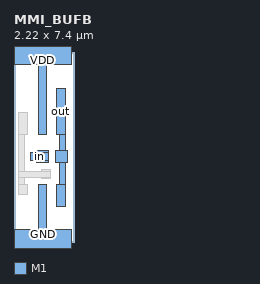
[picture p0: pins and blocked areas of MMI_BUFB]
MACRO MMI_BUFB
	CLASS CORE ;
	FOREIGN MMI_BUFB 0 0 ;
	SIZE 2.22 BY 7.4 ;
	SYMMETRY X Y ;
	SITE CORE1 ;
	PIN out
		DIRECTION output ;
		USE SIGNAL ;
		PORT
			LAYER M1 ;
			RECT 1.66 4.2 2 5.96 ;
			LAYER M1 ;
			RECT 1.77 3.555 2 4.2 ;
			LAYER M1 ;
			RECT 1.625 3.105 2.075 3.555 ;
			LAYER M1 ;
			RECT 1.77 2.23 2 3.105 ;
			LAYER M1 ;
			RECT 1.66 1.39 2 2.23 ;
		END
		AntennaDiffArea 1.3248 ;
	END out
	PIN GND
		DIRECTION inout ;
		USE GROUND ;
		PORT
			LAYER M1 ;
			RECT 0.94 0.5 1.28 2.23 ;
			LAYER M1 ;
			RECT 0 -0.5 2.22 0.5 ;
		END
	END GND
	PIN VDD
		DIRECTION inout ;
		USE POWER ;
		PORT
			LAYER M1 ;
			RECT 0 6.9 2.22 7.9 ;
			LAYER M1 ;
			RECT 0.94 4.2 1.28 6.9 ;
		END
	END VDD
	PIN in
		DIRECTION input ;
		USE SIGNAL ;
		PORT
			LAYER M1 ;
			RECT 0.885 3.5 1.335 3.555 ;
			LAYER M1 ;
			RECT 0.64 3.16 1.335 3.5 ;
			LAYER M1 ;
			RECT 0.885 3.105 1.335 3.16 ;
		END
		AntennaGateArea 0.2484 ;
	END in
	OBS
		LAYER M1 ;
		RECT 0.18 4.2 0.52 5.04 ;
		LAYER M1 ;
		RECT 0.18 2.755 0.41 4.2 ;
		LAYER M1 ;
		RECT 1.09 2.755 1.43 2.81 ;
		LAYER M1 ;
		RECT 0.18 2.525 1.43 2.755 ;
		LAYER M1 ;
		RECT 0.18 2.23 0.41 2.525 ;
		LAYER M1 ;
		RECT 1.09 2.47 1.43 2.525 ;
		LAYER M1 ;
		RECT 0.18 1.85 0.52 2.23 ;
	END
END MMI_BUFB
